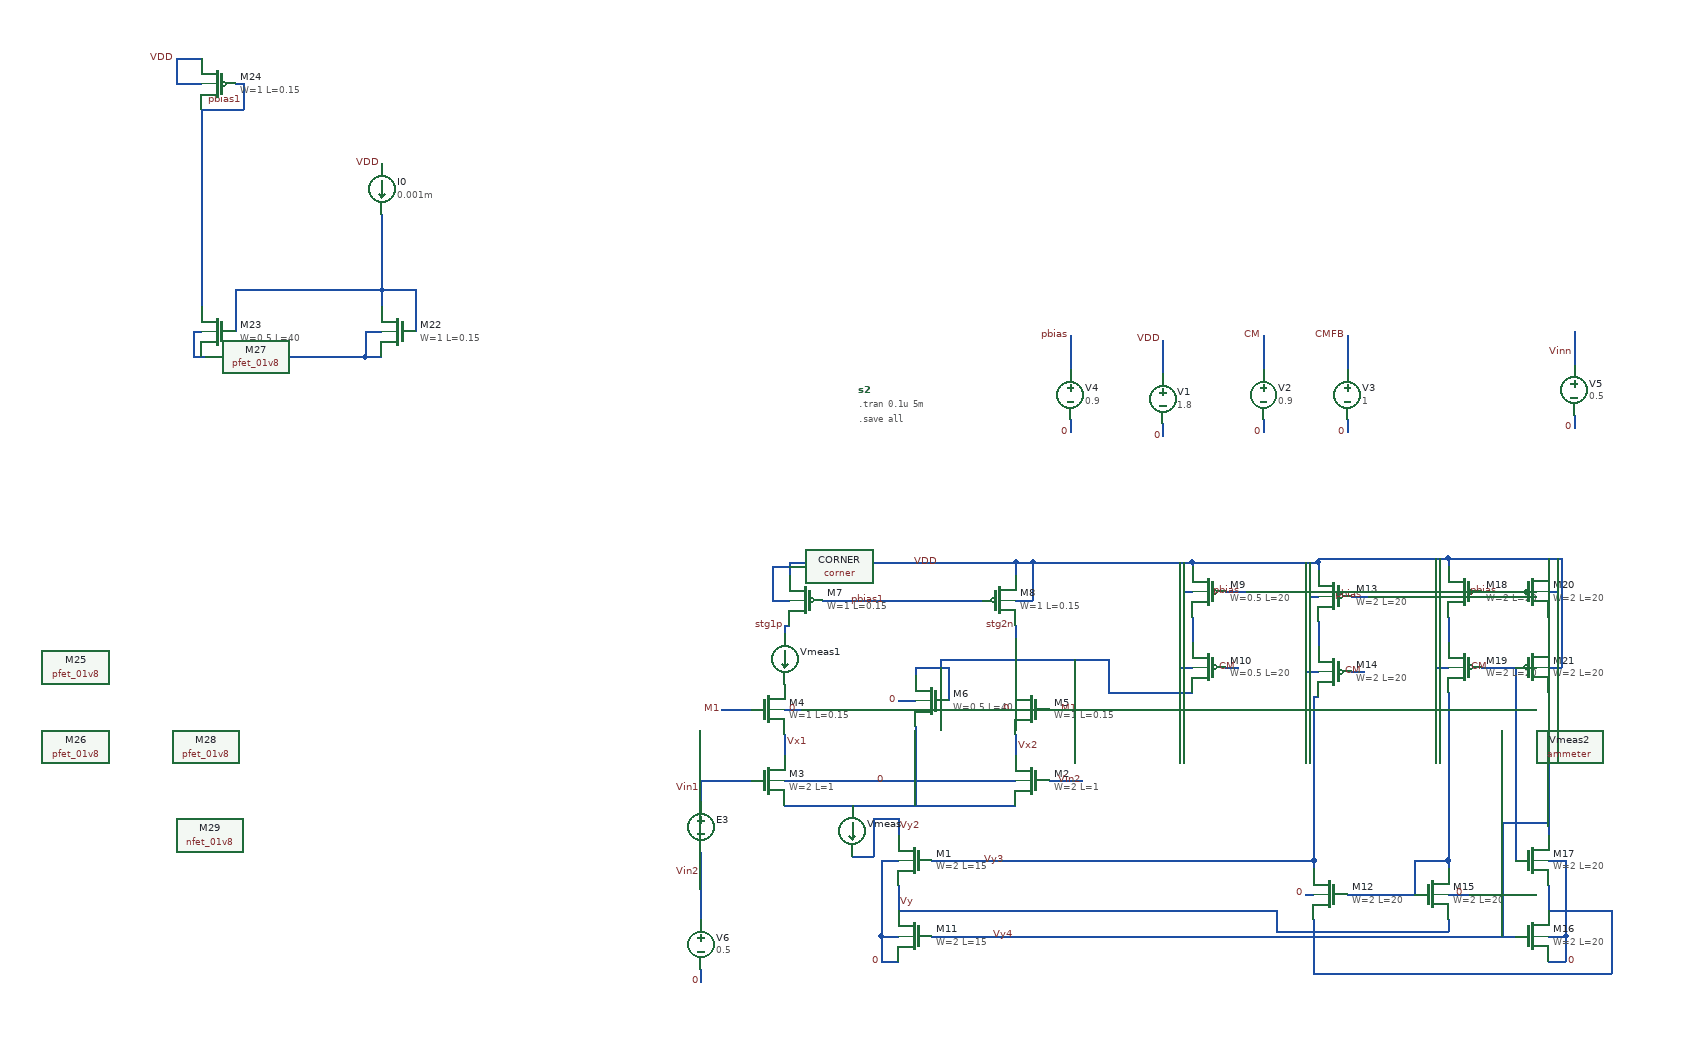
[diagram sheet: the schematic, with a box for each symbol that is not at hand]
v {xschem version=3.1.0 file_version=1.2
}
G {}
K {}
V {}
S {}
E {}
N -140 460 -140 490 {
lab=Vy}
N -160 520 -140 520 {
lab=0}
N -160 520 -160 550 {
lab=0}
N -160 550 -140 550 {
lab=0}
N -160 460 -160 520 {
lab=0}
N 175 -190 175 -150 {
lab=VDD}
N -160 430 -160 460 {
lab=0}
N -160 430 -140 430 {
lab=0}
N -275 365 0 365 {
lab=#net1}
N -275 335 -0 335 {
lab=0}
N -275 280 -275 305 {
lab=Vx1}
N 0 280 -0 305 {
lab=Vx2}
N -120 270 -120 365 {
lab=#net1}
N -80 200 -80 240 {
lab=M1}
N -120 200 -80 200 {
lab=M1}
N -120 200 -120 210 {
lab=M1}
N -275 250 -255 250 {
lab=0}
N -140 240 -120 240 {
lab=0}
N -5 250 0 250 {
lab=0}
N -230 120 -40 120 {
lab=pbias1}
N -275 150 -270 150 {
lab=stg1p}
N -270 75 -270 90 {
lab=VDD}
N -270 75 0 75 {
lab=VDD}
N 0 75 -0 90 {
lab=VDD}
N -290 120 -270 120 {
lab=VDD}
N -290 80 -290 120 {
lab=VDD}
N -290 80 -270 80 {
lab=VDD}
N -0 120 20 120 {
lab=VDD}
N 20 75 20 120 {
lab=VDD}
N -0 75 20 75 {
lab=VDD}
N -350 250 -315 250 {
lab=M1}
N 40 250 75 250 {
lab=M1}
N 20 75 210 75 {
lab=VDD}
N 210 75 210 80 {
lab=VDD}
N 200 110 210 110 {
lab=VDD}
N 200 75 200 110 {
lab=VDD}
N 210 140 210 170 {
lab=#net2}
N 195 200 210 200 {
lab=VDD}
N 195 75 195 200 {
lab=VDD}
N 110 230 210 230 {
lab=M1}
N 110 190 110 230 {
lab=M1}
N -90 190 110 190 {
lab=M1}
N -90 190 -90 200 {
lab=M1}
N 360 80 360 85 {
lab=VDD}
N 350 115 360 115 {
lab=VDD}
N 350 80 350 115 {
lab=VDD}
N 360 145 360 175 {
lab=#net3}
N 345 205 360 205 {
lab=VDD}
N 345 80 345 205 {
lab=VDD}
N 210 75 360 75 {
lab=VDD}
N 360 75 360 80 {
lab=VDD}
N 350 75 350 80 {
lab=VDD}
N 345 75 345 80 {
lab=VDD}
N -100 430 355 430 {
lab=Vy3}
N 355 430 355 440 {
lab=Vy3}
N 355 235 355 430 {
lab=Vy3}
N 355 235 360 235 {
lab=Vy3}
N 345 470 355 470 {
lab=0}
N 395 470 475 470 {
lab=#net4}
N 475 430 475 470 {
lab=#net4}
N 475 430 515 430 {
lab=#net4}
N 515 430 515 440 {
lab=#net4}
N -140 490 310 490 {
lab=Vy}
N 310 490 310 515 {
lab=Vy}
N 310 515 515 515 {
lab=Vy}
N 515 500 515 515 {
lab=Vy}
N 635 460 635 490 {
lab=#net5}
N 635 520 655 520 {
lab=0}
N 655 520 655 550 {
lab=0}
N 635 550 655 550 {
lab=0}
N 655 460 655 520 {
lab=0}
N 655 430 655 460 {
lab=0}
N 635 430 655 430 {
lab=0}
N -100 520 595 520 {
lab=Vy4}
N 580 385 580 520 {
lab=Vy4}
N 580 385 635 385 {
lab=Vy4}
N 635 385 635 400 {
lab=Vy4}
N 515 75 515 80 {
lab=VDD}
N 505 110 515 110 {
lab=VDD}
N 505 75 505 110 {
lab=VDD}
N 515 140 515 170 {
lab=#net6}
N 500 200 515 200 {
lab=VDD}
N 500 75 500 200 {
lab=VDD}
N 515 70 515 75 {
lab=VDD}
N 505 70 505 75 {
lab=VDD}
N 500 70 500 75 {
lab=VDD}
N 515 230 515 430 {
lab=#net4}
N 360 70 515 70 {
lab=VDD}
N 360 70 360 75 {
lab=VDD}
N 635 75 635 80 {
lab=VDD}
N 635 110 645 110 {
lab=VDD}
N 645 75 645 110 {
lab=VDD}
N 635 140 635 170 {
lab=#net7}
N 635 200 650 200 {
lab=VDD}
N 650 75 650 200 {
lab=VDD}
N 635 70 635 75 {
lab=VDD}
N 645 70 645 75 {
lab=VDD}
N 650 70 650 75 {
lab=VDD}
N 635 230 635 390 {
lab=Vy4}
N 515 70 650 70 {
lab=VDD}
N 250 200 265 200 {
lab=CM}
N 400 205 415 205 {
lab=CM}
N 555 200 600 200 {
lab=CM}
N 595 200 595 430 {
lab=CM}
N 555 110 595 110 {
lab=pbias}
N 400 115 420 115 {
lab=pbias}
N 250 110 275 110 {
lab=pbias}
N 70 190 70 250 {
lab=M1}
N 515 470 540 470 {
lab=0}
N 355 500 355 565 {
lab=#net5}
N 355 565 710 565 {
lab=#net5}
N 710 490 710 565 {
lab=#net5}
N 635 490 710 490 {
lab=#net5}
N 175 -90 175 -75 {
lab=0}
N 295 -195 295 -155 {
lab=CM}
N 295 -95 295 -80 {
lab=0}
N 395 -195 395 -155 {
lab=CMFB}
N 395 -95 395 -80 {
lab=0}
N -375 420 -375 445 {
lab=Vin2}
N -375 340 -375 360 {
lab=Vin1}
N 65 -195 65 -155 {
lab=pbias}
N 65 -95 65 -80 {
lab=0}
N 665 -200 665 -160 {
lab=Vinn}
N 665 -100 665 -85 {
lab=0}
N -195 425 -170 425 {
lab=Vy2}
N -170 380 -170 425 {
lab=Vy2}
N -170 380 -140 380 {
lab=Vy2}
N -140 380 -140 400 {
lab=Vy2}
N -275 150 -275 160 {
lab=stg1p}
N 0 150 0 165 {
lab=stg2n}
N -375 335 -315 335 {
lab=Vin1}
N -375 335 -375 340 {
lab=Vin1}
N -375 460 -375 500 {
lab=Vin2}
N -375 560 -375 575 {
lab=0}
N -375 445 -375 465 {
lab=Vin2}
N 40 335 80 335 {
lab=Vin2}
N -775 -200 -755 -200 {
lab=0}
N -775 -200 -775 -170 {
lab=0}
N -775 -170 -755 -170 {
lab=0}
N -715 -250 -715 -200 {
lab=#net8}
N -755 -250 -715 -250 {
lab=#net8}
N -755 -250 -755 -230 {
lab=#net8}
N -755 -340 -755 -250 {
lab=#net8}
N -970 -170 -775 -170 {
lab=0}
N -980 -200 -970 -200 {
lab=0}
N -980 -200 -980 -170 {
lab=0}
N -980 -170 -965 -170 {
lab=0}
N -930 -250 -755 -250 {
lab=#net8}
N -930 -250 -930 -200 {
lab=#net8}
N -970 -465 -970 -230 {
lab=pbias1}
N -970 -465 -920 -465 {
lab=pbias1}
N -920 -495 -920 -465 {
lab=pbias1}
N -930 -495 -920 -495 {
lab=pbias1}
N -1000 -495 -970 -495 {
lab=VDD}
N -1000 -525 -1000 -495 {
lab=VDD}
N -1000 -525 -970 -525 {
lab=VDD}
C {sky130_fd_pr/nfet_01v8.sym} -120 520 0 1 {name=M11
L=15
W=2
nf=1 
mult=1
ad="'int((nf+1)/2) * W/nf * 0.29'" 
pd="'2*int((nf+1)/2) * (W/nf + 0.29)'"
as="'int((nf+2)/2) * W/nf * 0.29'" 
ps="'2*int((nf+2)/2) * (W/nf + 0.29)'"
nrd="'0.29 / W'" nrs="'0.29 / W'"
sa=0 sb=0 sd=0
model=nfet_01v8
spiceprefix=X
}
C {devices/lab_pin.sym} -140 480 0 1 {name=p14 sig_type=std_logic lab=Vy}
C {devices/lab_pin.sym} -160 550 0 0 {name=p13 sig_type=std_logic lab=0}
C {sky130_fd_pr/corner.sym} -330 -145 0 0 {name=CORNER only_toplevel=false corner=tt}
C {devices/code_shown.sym} -187.5 -130 0 0 {name=s2 only_toplevel=false value="
.tran 0.1u 5m
.save all
"}
C {devices/vsource.sym} 175 -120 0 0 {name=V1 value=1.8}
C {devices/lab_pin.sym} 175 -190 0 0 {name=p8 sig_type=std_logic lab=VDD}
C {sky130_fd_pr/nfet_01v8.sym} -120 430 0 1 {name=M1
L=15
W=2
nf=1 
mult=1
ad="'int((nf+1)/2) * W/nf * 0.29'" 
pd="'2*int((nf+1)/2) * (W/nf + 0.29)'"
as="'int((nf+2)/2) * W/nf * 0.29'" 
ps="'2*int((nf+2)/2) * (W/nf + 0.29)'"
nrd="'0.29 / W'" nrs="'0.29 / W'"
sa=0 sb=0 sd=0
model=nfet_01v8
spiceprefix=X
}
C {sky130_fd_pr/nfet_01v8.sym} 20 335 0 1 {name=M2
L=1
W=2
nf=1 
mult=10
ad="'int((nf+1)/2) * W/nf * 0.29'" 
pd="'2*int((nf+1)/2) * (W/nf + 0.29)'"
as="'int((nf+2)/2) * W/nf * 0.29'" 
ps="'2*int((nf+2)/2) * (W/nf + 0.29)'"
nrd="'0.29 / W'" nrs="'0.29 / W'"
sa=0 sb=0 sd=0
model=nfet_01v8
spiceprefix=X
}
C {sky130_fd_pr/nfet_01v8.sym} -295 335 0 0 {name=M3
L=1
W=2
nf=1 
mult=10
ad="'int((nf+1)/2) * W/nf * 0.29'" 
pd="'2*int((nf+1)/2) * (W/nf + 0.29)'"
as="'int((nf+2)/2) * W/nf * 0.29'" 
ps="'2*int((nf+2)/2) * (W/nf + 0.29)'"
nrd="'0.29 / W'" nrs="'0.29 / W'"
sa=0 sb=0 sd=0
model=nfet_01v8
spiceprefix=X
}
C {devices/lab_pin.sym} -155 335 0 0 {name=p1 sig_type=std_logic lab=0}
C {sky130_fd_pr/nfet_01v8.sym} -295 250 0 0 {name=M4
L=0.15
W=1
nf=1 
mult=10
ad="'int((nf+1)/2) * W/nf * 0.29'" 
pd="'2*int((nf+1)/2) * (W/nf + 0.29)'"
as="'int((nf+2)/2) * W/nf * 0.29'" 
ps="'2*int((nf+2)/2) * (W/nf + 0.29)'"
nrd="'0.29 / W'" nrs="'0.29 / W'"
sa=0 sb=0 sd=0
model=nfet_01v8
spiceprefix=X
}
C {sky130_fd_pr/nfet_01v8.sym} 20 250 0 1 {name=M5
L=0.15
W=1
nf=1 
mult=1
ad="'int((nf+1)/2) * W/nf * 0.29'" 
pd="'2*int((nf+1)/2) * (W/nf + 0.29)'"
as="'int((nf+2)/2) * W/nf * 0.29'" 
ps="'2*int((nf+2)/2) * (W/nf + 0.29)'"
nrd="'0.29 / W'" nrs="'0.29 / W'"
sa=0 sb=0 sd=0
model=nfet_01v8
spiceprefix=X
}
C {sky130_fd_pr/nfet_01v8.sym} -100 240 0 1 {name=M6
L=40
W=0.5
nf=1 
mult=1
ad="'int((nf+1)/2) * W/nf * 0.29'" 
pd="'2*int((nf+1)/2) * (W/nf + 0.29)'"
as="'int((nf+2)/2) * W/nf * 0.29'" 
ps="'2*int((nf+2)/2) * (W/nf + 0.29)'"
nrd="'0.29 / W'" nrs="'0.29 / W'"
sa=0 sb=0 sd=0
model=nfet_01v8
spiceprefix=X
}
C {devices/lab_pin.sym} -260 250 0 0 {name=p2 sig_type=std_logic lab=0}
C {devices/lab_pin.sym} -140 240 0 0 {name=p3 sig_type=std_logic lab=0}
C {devices/lab_pin.sym} -5 250 0 0 {name=p4 sig_type=std_logic lab=0}
C {sky130_fd_pr/pfet_01v8.sym} -250 120 0 1 {name=M7
L=0.15
W=1
nf=1 
mult=1
ad="'int((nf+1)/2) * W/nf * 0.29'" 
pd="'2*int((nf+1)/2) * (W/nf + 0.29)'"
as="'int((nf+2)/2) * W/nf * 0.29'" 
ps="'2*int((nf+2)/2) * (W/nf + 0.29)'"
nrd="'0.29 / W'" nrs="'0.29 / W'"
sa=0 sb=0 sd=0
model=nfet_01v8
spiceprefix=X
}
C {sky130_fd_pr/pfet_01v8.sym} -20 120 0 0 {name=M8
L=0.15
W=1
nf=1 
mult=1
ad="'int((nf+1)/2) * W/nf * 0.29'" 
pd="'2*int((nf+1)/2) * (W/nf + 0.29)'"
as="'int((nf+2)/2) * W/nf * 0.29'" 
ps="'2*int((nf+2)/2) * (W/nf + 0.29)'"
nrd="'0.29 / W'" nrs="'0.29 / W'"
sa=0 sb=0 sd=0
model=nfet_01v8
spiceprefix=X
}
C {devices/lab_pin.sym} -350 250 0 0 {name=p7 sig_type=std_logic lab=M1}
C {devices/lab_pin.sym} 75 250 0 0 {name=p9 sig_type=std_logic lab=M1}
C {sky130_fd_pr/pfet_01v8.sym} 230 110 0 1 {name=M9
L=20
W=0.5
nf=1 
mult=1
ad="'int((nf+1)/2) * W/nf * 0.29'" 
pd="'2*int((nf+1)/2) * (W/nf + 0.29)'"
as="'int((nf+2)/2) * W/nf * 0.29'" 
ps="'2*int((nf+2)/2) * (W/nf + 0.29)'"
nrd="'0.29 / W'" nrs="'0.29 / W'"
sa=0 sb=0 sd=0
model=nfet_01v8
spiceprefix=X
}
C {sky130_fd_pr/pfet_01v8.sym} 230 200 0 1 {name=M10
L=20
W=0.5
nf=1 
mult=1
ad="'int((nf+1)/2) * W/nf * 0.29'" 
pd="'2*int((nf+1)/2) * (W/nf + 0.29)'"
as="'int((nf+2)/2) * W/nf * 0.29'" 
ps="'2*int((nf+2)/2) * (W/nf + 0.29)'"
nrd="'0.29 / W'" nrs="'0.29 / W'"
sa=0 sb=0 sd=0
model=nfet_01v8
spiceprefix=X
}
C {sky130_fd_pr/nfet_01v8.sym} 375 470 0 1 {name=M12
L=20
W=2
nf=1 
mult=1
ad="'int((nf+1)/2) * W/nf * 0.29'" 
pd="'2*int((nf+1)/2) * (W/nf + 0.29)'"
as="'int((nf+2)/2) * W/nf * 0.29'" 
ps="'2*int((nf+2)/2) * (W/nf + 0.29)'"
nrd="'0.29 / W'" nrs="'0.29 / W'"
sa=0 sb=0 sd=0
model=nfet_01v8
spiceprefix=X
}
C {sky130_fd_pr/pfet_01v8.sym} 380 115 0 1 {name=M13
L=20
W=2
nf=1 
mult=1
ad="'int((nf+1)/2) * W/nf * 0.29'" 
pd="'2*int((nf+1)/2) * (W/nf + 0.29)'"
as="'int((nf+2)/2) * W/nf * 0.29'" 
ps="'2*int((nf+2)/2) * (W/nf + 0.29)'"
nrd="'0.29 / W'" nrs="'0.29 / W'"
sa=0 sb=0 sd=0
model=nfet_01v8
spiceprefix=X
}
C {sky130_fd_pr/pfet_01v8.sym} 380 205 0 1 {name=M14
L=20
W=2
nf=1 
mult=1
ad="'int((nf+1)/2) * W/nf * 0.29'" 
pd="'2*int((nf+1)/2) * (W/nf + 0.29)'"
as="'int((nf+2)/2) * W/nf * 0.29'" 
ps="'2*int((nf+2)/2) * (W/nf + 0.29)'"
nrd="'0.29 / W'" nrs="'0.29 / W'"
sa=0 sb=0 sd=0
model=nfet_01v8
spiceprefix=X
}
C {sky130_fd_pr/nfet_01v8.sym} 495 470 0 0 {name=M15
L=20
W=2
nf=1 
mult=1
ad="'int((nf+1)/2) * W/nf * 0.29'" 
pd="'2*int((nf+1)/2) * (W/nf + 0.29)'"
as="'int((nf+2)/2) * W/nf * 0.29'" 
ps="'2*int((nf+2)/2) * (W/nf + 0.29)'"
nrd="'0.29 / W'" nrs="'0.29 / W'"
sa=0 sb=0 sd=0
model=nfet_01v8
spiceprefix=X
}
C {sky130_fd_pr/nfet_01v8.sym} 615 520 0 0 {name=M16
L=20
W=2
nf=1 
mult=1
ad="'int((nf+1)/2) * W/nf * 0.29'" 
pd="'2*int((nf+1)/2) * (W/nf + 0.29)'"
as="'int((nf+2)/2) * W/nf * 0.29'" 
ps="'2*int((nf+2)/2) * (W/nf + 0.29)'"
nrd="'0.29 / W'" nrs="'0.29 / W'"
sa=0 sb=0 sd=0
model=nfet_01v8
spiceprefix=X
}
C {devices/lab_pin.sym} 655 550 0 1 {name=p11 sig_type=std_logic lab=0}
C {sky130_fd_pr/nfet_01v8.sym} 615 430 0 0 {name=M17
L=20
W=2
nf=1 
mult=1
ad="'int((nf+1)/2) * W/nf * 0.29'" 
pd="'2*int((nf+1)/2) * (W/nf + 0.29)'"
as="'int((nf+2)/2) * W/nf * 0.29'" 
ps="'2*int((nf+2)/2) * (W/nf + 0.29)'"
nrd="'0.29 / W'" nrs="'0.29 / W'"
sa=0 sb=0 sd=0
model=nfet_01v8
spiceprefix=X
}
C {sky130_fd_pr/pfet_01v8.sym} 535 110 0 1 {name=M18
L=20
W=2
nf=1 
mult=1
ad="'int((nf+1)/2) * W/nf * 0.29'" 
pd="'2*int((nf+1)/2) * (W/nf + 0.29)'"
as="'int((nf+2)/2) * W/nf * 0.29'" 
ps="'2*int((nf+2)/2) * (W/nf + 0.29)'"
nrd="'0.29 / W'" nrs="'0.29 / W'"
sa=0 sb=0 sd=0
model=nfet_01v8
spiceprefix=X
}
C {sky130_fd_pr/pfet_01v8.sym} 535 200 0 1 {name=M19
L=20
W=2
nf=1 
mult=1
ad="'int((nf+1)/2) * W/nf * 0.29'" 
pd="'2*int((nf+1)/2) * (W/nf + 0.29)'"
as="'int((nf+2)/2) * W/nf * 0.29'" 
ps="'2*int((nf+2)/2) * (W/nf + 0.29)'"
nrd="'0.29 / W'" nrs="'0.29 / W'"
sa=0 sb=0 sd=0
model=nfet_01v8
spiceprefix=X
}
C {sky130_fd_pr/pfet_01v8.sym} 615 110 0 0 {name=M20
L=20
W=2
nf=1 
mult=1
ad="'int((nf+1)/2) * W/nf * 0.29'" 
pd="'2*int((nf+1)/2) * (W/nf + 0.29)'"
as="'int((nf+2)/2) * W/nf * 0.29'" 
ps="'2*int((nf+2)/2) * (W/nf + 0.29)'"
nrd="'0.29 / W'" nrs="'0.29 / W'"
sa=0 sb=0 sd=0
model=nfet_01v8
spiceprefix=X
}
C {sky130_fd_pr/pfet_01v8.sym} 615 200 0 0 {name=M21
L=20
W=2
nf=1 
mult=1
ad="'int((nf+1)/2) * W/nf * 0.29'" 
pd="'2*int((nf+1)/2) * (W/nf + 0.29)'"
as="'int((nf+2)/2) * W/nf * 0.29'" 
ps="'2*int((nf+2)/2) * (W/nf + 0.29)'"
nrd="'0.29 / W'" nrs="'0.29 / W'"
sa=0 sb=0 sd=0
model=nfet_01v8
spiceprefix=X
}
C {devices/lab_pin.sym} 265 200 0 0 {name=p12 sig_type=std_logic lab=CM}
C {devices/lab_pin.sym} 415 205 0 0 {name=p15 sig_type=std_logic lab=CM}
C {devices/lab_pin.sym} 565 200 0 0 {name=p16 sig_type=std_logic lab=CM}
C {devices/lab_pin.sym} 415 115 0 0 {name=p17 sig_type=std_logic lab=pbias}
C {devices/lab_pin.sym} 270 110 0 0 {name=p18 sig_type=std_logic lab=pbias}
C {devices/lab_pin.sym} 575 110 0 0 {name=p19 sig_type=std_logic lab=pbias}
C {devices/lab_pin.sym} -90 75 0 0 {name=p23 sig_type=std_logic lab=VDD}
C {devices/lab_pin.sym} 345 470 0 0 {name=p24 sig_type=std_logic lab=0}
C {devices/lab_pin.sym} 535 470 0 0 {name=p25 sig_type=std_logic lab=0}
C {devices/lab_pin.sym} 175 -75 0 0 {name=p10 sig_type=std_logic lab=0}
C {devices/vsource.sym} 295 -125 0 0 {name=V2 value=0.9}
C {devices/lab_pin.sym} 295 -195 0 0 {name=p21 sig_type=std_logic lab=CM}
C {devices/lab_pin.sym} 295 -80 0 0 {name=p22 sig_type=std_logic lab=0}
C {devices/vsource.sym} 395 -125 0 0 {name=V3 value=1}
C {devices/lab_pin.sym} 395 -195 0 0 {name=p26 sig_type=std_logic lab=CMFB}
C {devices/lab_pin.sym} 395 -80 0 0 {name=p27 sig_type=std_logic lab=0}
C {devices/vsource_arith.sym} -375 390 0 0 {name=E3 VOL="'0.1*cos(2*pi*time*1e3))'"}
C {devices/lab_pin.sym} -375 345 0 0 {name=p29 sig_type=std_logic lab=Vin1}
C {devices/vsource.sym} 65 -125 0 0 {name=V4 value=0.9}
C {devices/lab_pin.sym} 65 -195 0 0 {name=p30 sig_type=std_logic lab=pbias}
C {devices/lab_pin.sym} 65 -80 0 0 {name=p31 sig_type=std_logic lab=0}
C {devices/vsource.sym} 665 -130 0 0 {name=V5 value=0.5}
C {devices/lab_pin.sym} 665 -85 0 0 {name=p33 sig_type=std_logic lab=0}
C {devices/lab_pin.sym} 665 -175 0 0 {name=p34 sig_type=std_logic lab=Vinn}
C {devices/lab_pin.sym} -275 150 0 0 {name=p32 sig_type=std_logic lab=stg1p}
C {devices/lab_pin.sym} 0 150 0 0 {name=p35 sig_type=std_logic lab=stg2n}
C {devices/lab_pin.sym} -140 390 0 1 {name=p36 sig_type=std_logic lab=Vy2}
C {devices/lab_pin.sym} -275 290 0 1 {name=p37 sig_type=std_logic lab=Vx1}
C {devices/lab_pin.sym} 0 295 0 1 {name=p38 sig_type=std_logic lab=Vx2}
C {devices/lab_pin.sym} -40 430 0 1 {name=p39 sig_type=std_logic lab=Vy3}
C {devices/ammeter.sym} -195 395 0 0 {name=Vmeas}
C {devices/ammeter.sym} -275 190 0 0 {name=Vmeas1}
C {devices/ammeter.sym} 0 190 0 0 {name=Vmeas2}
C {devices/lab_pin.sym} -30 520 0 1 {name=p40 sig_type=std_logic lab=Vy4}
C {devices/vsource.sym} -375 530 0 0 {name=V6 value=0.5}
C {devices/lab_pin.sym} -375 575 0 0 {name=p6 sig_type=std_logic lab=0}
C {devices/lab_pin.sym} -375 445 0 0 {name=p5 sig_type=std_logic lab=Vin2}
C {devices/lab_pin.sym} 80 335 0 0 {name=p28 sig_type=std_logic lab=Vin2}
C {sky130_fd_pr/nfet_01v8.sym} -735 -200 0 1 {name=M22
L=0.15
W=1
nf=1 
mult=10
ad="'int((nf+1)/2) * W/nf * 0.29'" 
pd="'2*int((nf+1)/2) * (W/nf + 0.29)'"
as="'int((nf+2)/2) * W/nf * 0.29'" 
ps="'2*int((nf+2)/2) * (W/nf + 0.29)'"
nrd="'0.29 / W'" nrs="'0.29 / W'"
sa=0 sb=0 sd=0
model=nfet_01v8
spiceprefix=X
}
C {devices/isource.sym} -755 -370 0 0 {name=I0 value=0.001m}
C {devices/lab_pin.sym} -920 -475 0 0 {name=p41 sig_type=std_logic lab=pbias1}
C {devices/lab_pin.sym} -755 -400 0 0 {name=p42 sig_type=std_logic lab=VDD}
C {sky130_fd_pr/nfet_01v8.sym} -950 -200 0 1 {name=M23
L=40
W=0.5
nf=1 
mult=1
ad="'int((nf+1)/2) * W/nf * 0.29'" 
pd="'2*int((nf+1)/2) * (W/nf + 0.29)'"
as="'int((nf+2)/2) * W/nf * 0.29'" 
ps="'2*int((nf+2)/2) * (W/nf + 0.29)'"
nrd="'0.29 / W'" nrs="'0.29 / W'"
sa=0 sb=0 sd=0
model=nfet_01v8
spiceprefix=X
}
C {sky130_fd_pr/pfet_01v8.sym} -950 -495 0 1 {name=M24
L=0.15
W=1
nf=1
mult=1
ad="'int((nf+1)/2) * W/nf * 0.29'" 
pd="'2*int((nf+1)/2) * (W/nf + 0.29)'"
as="'int((nf+2)/2) * W/nf * 0.29'" 
ps="'2*int((nf+2)/2) * (W/nf + 0.29)'"
nrd="'0.29 / W'" nrs="'0.29 / W'"
sa=0 sb=0 sd=0
model=pfet_01v8
spiceprefix=X
}
C {devices/lab_pin.sym} -155 120 0 0 {name=p20 sig_type=std_logic lab=pbias1}
C {devices/lab_pin.sym} -900 -170 0 0 {name=p43 sig_type=std_logic lab=0}
C {devices/lab_pin.sym} -1000 -525 0 0 {name=p44 sig_type=std_logic lab=VDD}
C {sky130_fd_pr/pfet_01v8.sym} -1120 200 0 1 {name=M25
L=0.15
W=1
nf=1
mult=1
ad="'int((nf+1)/2) * W/nf * 0.29'" 
pd="'2*int((nf+1)/2) * (W/nf + 0.29)'"
as="'int((nf+2)/2) * W/nf * 0.29'" 
ps="'2*int((nf+2)/2) * (W/nf + 0.29)'"
nrd="'0.29 / W'" nrs="'0.29 / W'"
sa=0 sb=0 sd=0
model=pfet_01v8
spiceprefix=X
}
C {sky130_fd_pr/pfet_01v8.sym} -1120 295 0 1 {name=M26
L=0.15
W=1
nf=1
mult=1
ad="'int((nf+1)/2) * W/nf * 0.29'" 
pd="'2*int((nf+1)/2) * (W/nf + 0.29)'"
as="'int((nf+2)/2) * W/nf * 0.29'" 
ps="'2*int((nf+2)/2) * (W/nf + 0.29)'"
nrd="'0.29 / W'" nrs="'0.29 / W'"
sa=0 sb=0 sd=0
model=pfet_01v8
spiceprefix=X
}
C {sky130_fd_pr/pfet_01v8.sym} -965 200 0 0 {name=M27
L=0.15
W=1
nf=1
mult=1
ad="'int((nf+1)/2) * W/nf * 0.29'" 
pd="'2*int((nf+1)/2) * (W/nf + 0.29)'"
as="'int((nf+2)/2) * W/nf * 0.29'" 
ps="'2*int((nf+2)/2) * (W/nf + 0.29)'"
nrd="'0.29 / W'" nrs="'0.29 / W'"
sa=0 sb=0 sd=0
model=pfet_01v8
spiceprefix=X
}
C {sky130_fd_pr/pfet_01v8.sym} -965 295 0 0 {name=M28
L=0.15
W=1
nf=1
mult=1
ad="'int((nf+1)/2) * W/nf * 0.29'" 
pd="'2*int((nf+1)/2) * (W/nf + 0.29)'"
as="'int((nf+2)/2) * W/nf * 0.29'" 
ps="'2*int((nf+2)/2) * (W/nf + 0.29)'"
nrd="'0.29 / W'" nrs="'0.29 / W'"
sa=0 sb=0 sd=0
model=pfet_01v8
spiceprefix=X
}
C {sky130_fd_pr/nfet_01v8.sym} -960 400 0 0 {name=M29
L=0.15
W=1
nf=1 
mult=10
ad="'int((nf+1)/2) * W/nf * 0.29'" 
pd="'2*int((nf+1)/2) * (W/nf + 0.29)'"
as="'int((nf+2)/2) * W/nf * 0.29'" 
ps="'2*int((nf+2)/2) * (W/nf + 0.29)'"
nrd="'0.29 / W'" nrs="'0.29 / W'"
sa=0 sb=0 sd=0
model=nfet_01v8
spiceprefix=X
}
